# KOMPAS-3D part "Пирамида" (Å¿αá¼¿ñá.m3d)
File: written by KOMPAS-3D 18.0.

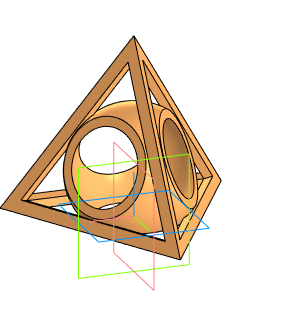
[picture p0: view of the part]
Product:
- Part/product: Пирамида

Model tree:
1. Операция без истории:1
